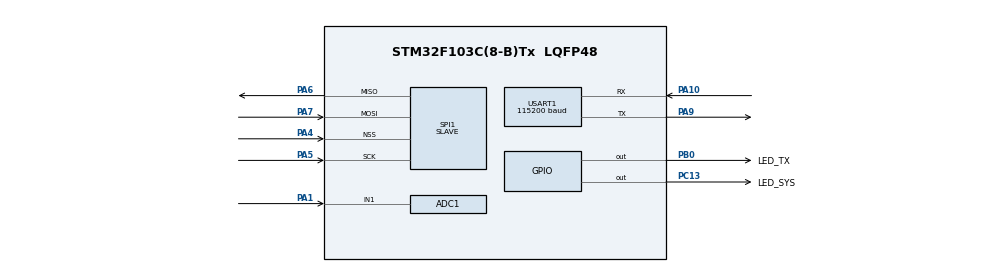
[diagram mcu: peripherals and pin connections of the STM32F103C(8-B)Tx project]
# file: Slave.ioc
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ADC1.Channel-0\#ChannelRegularConversion=ADC_CHANNEL_1
ADC1.NbrOfConversionFlag=1
ADC1.Rank-0\#ChannelRegularConversion=1
ADC1.SamplingTime-0\#ChannelRegularConversion=ADC_SAMPLETIME_1CYCLE_5
ADC1.master=1
Mcu.Family=STM32F1
Mcu.Name=STM32F103C(8-B)Tx
Mcu.Package=LQFP48
NVIC.PriorityGroup=NVIC_PRIORITYGROUP_4
PA1.Signal=ADCx_IN1
PA10.Mode=Asynchronous
PA10.Signal=USART1_RX
PA13.Mode=Serial_Wire
PA13.Signal=SYS_JTMS-SWDIO
PA14.Mode=Serial_Wire
PA14.Signal=SYS_JTCK-SWCLK
PA4.Mode=NSS_Signal_Hard_Input
PA4.Signal=SPI1_NSS
PA5.Mode=Full_Duplex_Slave
PA5.Signal=SPI1_SCK
PA6.Mode=Full_Duplex_Slave
PA6.Signal=SPI1_MISO
PA7.Mode=Full_Duplex_Slave
PA7.Signal=SPI1_MOSI
PA9.Mode=Asynchronous
PA9.Signal=USART1_TX
PB0.GPIO_Label=LED_TX
PB0.Signal=GPIO_Output
PC13-TAMPER-RTC.GPIO_Label=LED_SYS
PC13-TAMPER-RTC.Signal=GPIO_Output
PC14-OSC32_IN.Mode=LSE-External-Oscillator
PC14-OSC32_IN.Signal=RCC_OSC32_IN
PC15-OSC32_OUT.Mode=LSE-External-Oscillator
PC15-OSC32_OUT.Signal=RCC_OSC32_OUT
PD0-OSC_IN.Mode=HSE-External-Oscillator
PD0-OSC_IN.Signal=RCC_OSC_IN
PD1-OSC_OUT.Mode=HSE-External-Oscillator
PD1-OSC_OUT.Signal=RCC_OSC_OUT
ProjectManager.HeapSize=0x200
ProjectManager.StackSize=0x400
ProjectManager.TargetToolchain=MDK-ARM V5.32
RCC.ADCPresc=RCC_ADCPCLK2_DIV6
RCC.AHBFreq_Value=72000000
RCC.APB1CLKDivider=RCC_HCLK_DIV2
RCC.APB1Freq_Value=36000000
RCC.APB1TimFreq_Value=72000000
RCC.APB2Freq_Value=72000000
RCC.APB2TimFreq_Value=72000000
RCC.HCLKFreq_Value=72000000
RCC.PLLMUL=RCC_PLL_MUL9
RCC.PLLSourceVirtual=RCC_PLLSOURCE_HSE
RCC.SYSCLKFreq_VALUE=72000000
RCC.SYSCLKSource=RCC_SYSCLKSOURCE_PLLCLK
RCC.USBFreq_Value=72000000
SH.ADCx_IN1.0=ADC1_IN1,IN1
SPI1.CLKPhase=SPI_PHASE_1EDGE
SPI1.CLKPolarity=SPI_POLARITY_LOW
SPI1.DataSize=SPI_DATASIZE_8BIT
SPI1.Direction=SPI_DIRECTION_2LINES
SPI1.FirstBit=SPI_FIRSTBIT_MSB
SPI1.Mode=SPI_MODE_SLAVE
SPI1.NSS=SPI_NSS_HARD_INPUT
SPI1.VirtualNSS=VM_NSSHARD
SPI1.VirtualType=VM_SLAVE
USART1.BaudRate=115200
USART1.Parity=PARITY_NONE
USART1.StopBits=STOPBITS_1
USART1.VirtualMode=VM_ASYNC
USART1.VirtualType=VM_ASYNC
USART1.WordLength=WORDLENGTH_8B
board=custom

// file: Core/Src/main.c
/* USER CODE BEGIN Header */
/**
  ******************************************************************************
  * @file           : main.c
  * @brief          : TPMS Slave - Tire Pressure Sensor Node (Proteus)
  ******************************************************************************
  */
/* USER CODE END Header */
#include "main.h"
#include "adc.h"
#include "spi.h"
#include "usart.h"
#include "gpio.h"

/* USER CODE BEGIN Includes */
#include <stdio.h>
/* USER CODE END Includes */

/* USER CODE BEGIN PD */
#define TX_HEADER  0x5A
/* USER CODE END PD */

void SystemClock_Config(void);

int main(void)
{

  HAL_Init();
  SystemClock_Config();

  MX_GPIO_Init();
  MX_SPI1_Init();
  /* Reconfigure PA6 as GPIO output for bit-bang MISO */
  GPIO_InitTypeDef gpio = {0};
  gpio.Pin = GPIO_PIN_6;
  gpio.Mode = GPIO_MODE_OUTPUT_PP;
  gpio.Speed = GPIO_SPEED_FREQ_HIGH;
  HAL_GPIO_Init(GPIOA, &gpio);
  MX_USART1_UART_Init();
  huart1.Init.BaudRate = 9600;
  HAL_UART_Init(&huart1);
  MX_ADC1_Init();
  /* PA2 as analog for temperature potentiometer */
  { GPIO_InitTypeDef g={0}; g.Pin=GPIO_PIN_2; g.Mode=GPIO_MODE_ANALOG; HAL_GPIO_Init(GPIOA,&g); }
  uint8_t temperature = 25;
  /* USER CODE BEGIN 2 */
  HAL_GPIO_WritePin(LED_SYS_GPIO_Port, LED_SYS_Pin, GPIO_PIN_SET);
  HAL_Delay(500);
  HAL_GPIO_WritePin(LED_SYS_GPIO_Port, LED_SYS_Pin, GPIO_PIN_RESET);

  char msg[] = "Slave ready\r\n";
  HAL_UART_Transmit(&huart1, (uint8_t*)msg, sizeof(msg)-1, 100);
  /* USER CODE END 2 */

  /* Infinite loop */
  while (1)
  {

  /* USER CODE BEGIN 3 */
    char dbg[64];
    int len;
    static uint16_t pressure = 0, loop_count = 0;

    /* Read pressure ADC (CH1) */
    ADC1->SQR3 = ADC_CHANNEL_1;
    HAL_ADC_Start(&hadc1);
    HAL_ADC_PollForConversion(&hadc1, 10);
    uint16_t adc_val = HAL_ADC_GetValue(&hadc1);
    pressure = (uint32_t)adc_val * 600 / 4095;

    /* Read temperature ADC (CH2) every 4th loop */
    if (loop_count % 4 == 0) {
      ADC1->SQR3 = ADC_CHANNEL_2;
      HAL_ADC_Start(&hadc1);
      HAL_ADC_PollForConversion(&hadc1, 10);
      uint16_t t_raw = HAL_ADC_GetValue(&hadc1);
      temperature = (uint8_t)((uint32_t)t_raw * 60 / 4095);
    }

    /* Build 6-byte tx: sync + header + P_hi + P_lo + temp + checksum */
    uint8_t tx[6];
    tx[0] = 0x00;
    tx[1] = TX_HEADER;
    tx[2] = pressure >> 8;
    tx[3] = pressure & 0xFF;
    tx[4] = temperature;
    tx[5] = tx[1] + tx[2] + tx[3] + tx[4];

    /* Wait for NSS low */
    while (HAL_GPIO_ReadPin(GPIOA, GPIO_PIN_4) == GPIO_PIN_SET);

    /* Software SPI slave */
    int b, bit;
    for (b = 0; b < 6; b++) {
      uint8_t byte = tx[b];
      for (bit = 0; bit < 8; bit++) {
        while (HAL_GPIO_ReadPin(GPIOA, GPIO_PIN_5) == GPIO_PIN_RESET);
        if (byte & 0x80) HAL_GPIO_WritePin(GPIOA, GPIO_PIN_6, GPIO_PIN_SET);
        else             HAL_GPIO_WritePin(GPIOA, GPIO_PIN_6, GPIO_PIN_RESET);
        byte <<= 1;
        while (HAL_GPIO_ReadPin(GPIOA, GPIO_PIN_5) == GPIO_PIN_SET);
      }
    }
    HAL_GPIO_TogglePin(LED_TX_GPIO_Port, LED_TX_Pin);

    /* Wait for NSS high */
    while (HAL_GPIO_ReadPin(GPIOA, GPIO_PIN_4) == GPIO_PIN_RESET);

    /* Debug */
    len = sprintf(dbg, "P=%3ukPa T=%uC\r\n", pressure, temperature);
    HAL_UART_Transmit(&huart1, (uint8_t*)dbg, len, 100);
    loop_count++;
    HAL_UART_Transmit(&huart1, (uint8_t*)dbg, len, 100);
  }
  /* USER CODE END 3 */
}

void SystemClock_Config(void)
{
  RCC_OscInitTypeDef RCC_OscInitStruct = {0};
  RCC_ClkInitTypeDef RCC_ClkInitStruct = {0};

  RCC_OscInitStruct.OscillatorType = RCC_OSCILLATORTYPE_HSI;
  RCC_OscInitStruct.HSIState = RCC_HSI_ON;
  RCC_OscInitStruct.HSEState = RCC_HSE_OFF;
  RCC_OscInitStruct.PLL.PLLState = RCC_PLL_NONE;
  if (HAL_RCC_OscConfig(&RCC_OscInitStruct) != HAL_OK) Error_Handler();

  RCC_ClkInitStruct.ClockType = RCC_CLOCKTYPE_HCLK|RCC_CLOCKTYPE_SYSCLK
                              |RCC_CLOCKTYPE_PCLK1|RCC_CLOCKTYPE_PCLK2;
  RCC_ClkInitStruct.SYSCLKSource = RCC_SYSCLKSOURCE_HSI;
  RCC_ClkInitStruct.AHBCLKDivider = RCC_SYSCLK_DIV1;
  RCC_ClkInitStruct.APB1CLKDivider = RCC_HCLK_DIV1;
  RCC_ClkInitStruct.APB2CLKDivider = RCC_HCLK_DIV1;
  if (HAL_RCC_ClockConfig(&RCC_ClkInitStruct, FLASH_LATENCY_0) != HAL_OK) Error_Handler();
}

void Error_Handler(void)
{
  __disable_irq();
  while (1) {}
}
